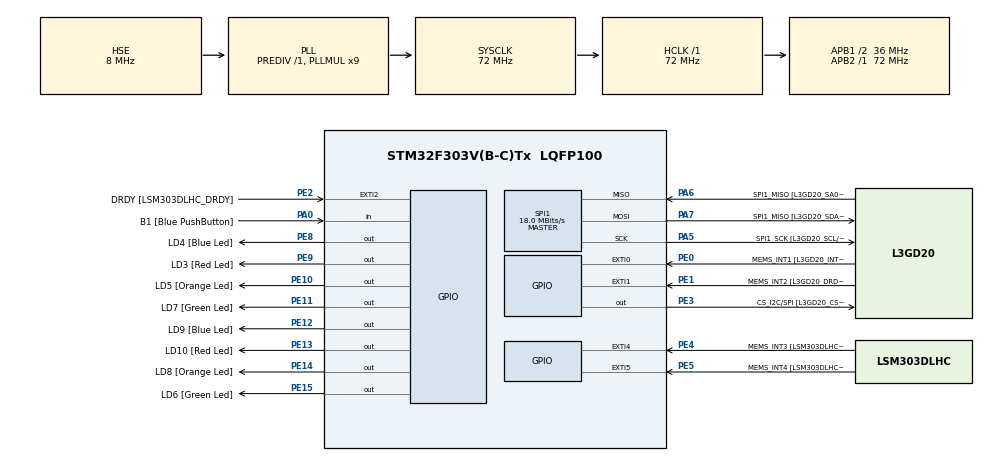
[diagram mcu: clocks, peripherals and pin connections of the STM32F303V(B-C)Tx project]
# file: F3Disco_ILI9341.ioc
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Mcu.Family=STM32F3
Mcu.Name=STM32F303V(B-C)Tx
Mcu.Package=LQFP100
NVIC.PriorityGroup=NVIC_PRIORITYGROUP_0
PA0.GPIO_Label=B1 [Blue PushButton]
PA0.GPIO_Mode=GPIO_MODE_INPUT
PA0.GPIO_PuPd=GPIO_NOPULL
PA0.Signal=GPIO_Input
PA11.GPIO_Label=DM
PA11.GPIO_Mode=GPIO_MODE_AF_PP
PA11.GPIO_PuPd=GPIO_NOPULL
PA11.GPIO_Speed=GPIO_SPEED_LOW
PA11.Signal=USB_DM
PA12.GPIO_Label=DP
PA12.GPIO_Mode=GPIO_MODE_AF_PP
PA12.GPIO_PuPd=GPIO_NOPULL
PA12.GPIO_Speed=GPIO_SPEED_LOW
PA12.Signal=USB_DP
PA13.GPIO_Label=SWDIO
PA13.Mode=Trace-Asynchronous_SW
PA13.Signal=SYS_JTMS-SWDIO
PA14.GPIO_Label=SWCLK
PA14.Mode=Trace-Asynchronous_SW
PA14.Signal=SYS_JTCK-SWCLK
PA5.GPIO_Label=SPI1_SCK [L3GD20_SCL/SPC]
PA5.GPIO_Mode=GPIO_MODE_AF_PP
PA5.GPIO_PuPd=GPIO_NOPULL
PA5.GPIO_Speed=GPIO_SPEED_LOW
PA5.Mode=Full_Duplex_Master
PA5.Signal=SPI1_SCK
PA6.GPIO_Label=SPI1_MISO [L3GD20_SA0/SDO]
PA6.GPIO_Mode=GPIO_MODE_AF_PP
PA6.GPIO_PuPd=GPIO_NOPULL
PA6.GPIO_Speed=GPIO_SPEED_LOW
PA6.Mode=Full_Duplex_Master
PA6.Signal=SPI1_MISO
PA7.GPIO_Label=SPI1_MISO [L3GD20_SDA/SDI/SDO]
PA7.GPIO_Mode=GPIO_MODE_AF_PP
PA7.GPIO_PuPd=GPIO_NOPULL
PA7.GPIO_Speed=GPIO_SPEED_LOW
PA7.Mode=Full_Duplex_Master
PA7.Signal=SPI1_MOSI
PB3.GPIO_Label=SWO
PB3.Mode=Trace-Asynchronous_SW
PB3.Signal=SYS_JTDO-TRACESWO
PB6.GPIO_FM6=__NULL
PB6.GPIO_Label=I2C1_SCL [LSM303DLHC_SCL]
PB6.GPIO_Mode=GPIO_MODE_AF_OD
PB6.GPIO_PuPd=GPIO_NOPULL
PB6.GPIO_PuPdOD=GPIO_PULLUP
PB6.GPIO_Speed=GPIO_SPEED_LOW
PB6.Signal=I2C1_SCL
PB7.GPIO_FM7=__NULL
PB7.GPIO_Label=I2C1_SDA [LSM303DLHC_SDA]
PB7.GPIO_Mode=GPIO_MODE_AF_OD
PB7.GPIO_PuPd=GPIO_NOPULL
PB7.GPIO_PuPdOD=GPIO_PULLUP
PB7.GPIO_Speed=GPIO_SPEED_LOW
PB7.Signal=I2C1_SDA
PC14-OSC32_IN.GPIO_Label=OSC32_IN
PC14-OSC32_IN.Signal=RCC_OSC32_IN
PC15-OSC32_OUT.GPIO_Label=OSC32_OUT
PC15-OSC32_OUT.Signal=RCC_OSC32_OUT
PE0.GPIO_Label=MEMS_INT1 [L3GD20_INT1]
PE0.GPIO_ModeDefaultEXTI=GPIO_MODE_EVT_RISING
PE0.GPIO_PuPd=GPIO_NOPULL
PE0.Signal=GPXTI0
PE1.GPIO_Label=MEMS_INT2 [L3GD20_DRDY/INT2]
PE1.GPIO_ModeDefaultEXTI=GPIO_MODE_EVT_RISING
PE1.GPIO_PuPd=GPIO_NOPULL
PE1.Signal=GPXTI1
PE10.GPIO_Label=LD5 [Orange Led]
PE10.GPIO_ModeDefaultOutputPP=GPIO_MODE_OUTPUT_PP
PE10.GPIO_PuPd=GPIO_NOPULL
PE10.GPIO_Speed=GPIO_SPEED_LOW
PE10.Signal=GPIO_Output
PE11.GPIO_Label=LD7 [Green Led]
PE11.GPIO_ModeDefaultOutputPP=GPIO_MODE_OUTPUT_PP
PE11.GPIO_PuPd=GPIO_NOPULL
PE11.GPIO_Speed=GPIO_SPEED_LOW
PE11.Signal=GPIO_Output
PE12.GPIO_Label=LD9 [Blue Led]
PE12.GPIO_ModeDefaultOutputPP=GPIO_MODE_OUTPUT_PP
PE12.GPIO_PuPd=GPIO_NOPULL
PE12.GPIO_Speed=GPIO_SPEED_LOW
PE12.Signal=GPIO_Output
PE13.GPIO_Label=LD10 [Red Led]
PE13.GPIO_ModeDefaultOutputPP=GPIO_MODE_OUTPUT_PP
PE13.GPIO_PuPd=GPIO_NOPULL
PE13.GPIO_Speed=GPIO_SPEED_LOW
PE13.Signal=GPIO_Output
PE14.GPIO_Label=LD8 [Orange Led]
PE14.GPIO_ModeDefaultOutputPP=GPIO_MODE_OUTPUT_PP
PE14.GPIO_PuPd=GPIO_NOPULL
PE14.GPIO_Speed=GPIO_SPEED_LOW
PE14.Signal=GPIO_Output
PE15.GPIO_Label=LD6 [Green Led]
PE15.GPIO_ModeDefaultOutputPP=GPIO_MODE_OUTPUT_PP
PE15.GPIO_PuPd=GPIO_NOPULL
PE15.GPIO_Speed=GPIO_SPEED_LOW
PE15.Signal=GPIO_Output
PE2.GPIO_Label=DRDY [LSM303DLHC_DRDY]
PE2.GPIO_ModeDefaultEXTI=GPIO_MODE_EVT_RISING
PE2.GPIO_PuPd=GPIO_NOPULL
PE2.Signal=GPXTI2
PE3.GPIO_Label=CS_I2C/SPI [L3GD20_CS_I2C/SPI]
PE3.GPIO_ModeDefaultOutputPP=GPIO_MODE_OUTPUT_PP
PE3.GPIO_PuPd=GPIO_NOPULL
PE3.GPIO_Speed=GPIO_SPEED_LOW
PE3.Signal=GPIO_Output
PE4.GPIO_Label=MEMS_INT3 [LSM303DLHC_INT1]
PE4.GPIO_ModeDefaultEXTI=GPIO_MODE_EVT_RISING
PE4.GPIO_PuPd=GPIO_NOPULL
PE4.Signal=GPXTI4
PE5.GPIO_Label=MEMS_INT4 [LSM303DLHC_INT2]
PE5.GPIO_ModeDefaultEXTI=GPIO_MODE_EVT_RISING
PE5.GPIO_PuPd=GPIO_NOPULL
PE5.Signal=GPXTI5
PE8.GPIO_Label=LD4 [Blue Led]
PE8.GPIO_ModeDefaultOutputPP=GPIO_MODE_OUTPUT_PP
PE8.GPIO_PuPd=GPIO_NOPULL
PE8.GPIO_Speed=GPIO_SPEED_LOW
PE8.Signal=GPIO_Output
PE9.GPIO_Label=LD3 [Red Led]
PE9.GPIO_ModeDefaultOutputPP=GPIO_MODE_OUTPUT_PP
PE9.GPIO_PuPd=GPIO_NOPULL
PE9.GPIO_Speed=GPIO_SPEED_LOW
PE9.Signal=GPIO_Output
PF0-OSC_IN.Mode=HSE-External-Oscillator
PF0-OSC_IN.Signal=RCC_OSC_IN
PF1-OSC_OUT.GPIO_Label=OSC_OUT
PF1-OSC_OUT.Mode=HSE-External-Oscillator
PF1-OSC_OUT.Signal=RCC_OSC_OUT
ProjectManager.TargetToolchain=MDK-ARM V5
RCC.AHBFreq_Value=72000000
RCC.APB1CLKDivider=RCC_HCLK_DIV2
RCC.APB1Freq_Value=36000000
RCC.APB1TimFreq_Value=72000000
RCC.APB2Freq_Value=72000000
RCC.APB2TimFreq_Value=72000000
RCC.CortexFreq_Value=9000000
RCC.HCLKFreq_Value=72000000
RCC.HSE_VALUE=8000000
RCC.HSIState=RCC_HSI_ON
RCC.HSI_VALUE=8000000
RCC.LSE_VALUE=32768
RCC.PLLMUL=RCC_PLL_MUL9
RCC.PLLSourceVirtual=RCC_PLLSOURCE_HSE
RCC.SYSCLKFreq_VALUE=72000000
RCC.SYSCLKSource=RCC_SYSCLKSOURCE_PLLCLK
RCC.SYSCLKSourceVirtual=RCC_SYSCLKSOURCE_PLLCLK
RCC.USBFreq_Value=72000000
SPI1.BaudRatePrescaler=SPI_BAUDRATEPRESCALER_4
SPI1.CalculateBaudRate=18.0 MBits/s
SPI1.DataSize=SPI_DATASIZE_8BIT
SPI1.Mode=SPI_MODE_MASTER

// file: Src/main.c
/**
  ******************************************************************************
  * File Name          : main.c
  * Date               : 14/05/2015 17:09:52
  * Description        : Main program body
  ******************************************************************************
  *
  * COPYRIGHT(c) 2015 STMicroelectronics
  *
  * Redistribution and use in source and binary forms, with or without modification,
  * are permitted provided that the following conditions are met:
  *   1. Redistributions of source code must retain the above copyright notice,
  *      this list of conditions and the following disclaimer.
  *   2. Redistributions in binary form must reproduce the above copyright notice,
  *      this list of conditions and the following disclaimer in the documentation
  *      and/or other materials provided with the distribution.
  *   3. Neither the name of STMicroelectronics nor the names of its contributors
  *      may be used to endorse or promote products derived from this software
  *      without specific prior written permission.
  *
  * THIS SOFTWARE IS PROVIDED BY THE COPYRIGHT HOLDERS AND CONTRIBUTORS "AS IS"
  * AND ANY EXPRESS OR IMPLIED WARRANTIES, INCLUDING, BUT NOT LIMITED TO, THE
  * IMPLIED WARRANTIES OF MERCHANTABILITY AND FITNESS FOR A PARTICULAR PURPOSE ARE
  * DISCLAIMED. IN NO EVENT SHALL THE COPYRIGHT HOLDER OR CONTRIBUTORS BE LIABLE
  * FOR ANY DIRECT, INDIRECT, INCIDENTAL, SPECIAL, EXEMPLARY, OR CONSEQUENTIAL
  * DAMAGES (INCLUDING, BUT NOT LIMITED TO, PROCUREMENT OF SUBSTITUTE GOODS OR
  * SERVICES; LOSS OF USE, DATA, OR PROFITS; OR BUSINESS INTERRUPTION) HOWEVER
  * CAUSED AND ON ANY THEORY OF LIABILITY, WHETHER IN CONTRACT, STRICT LIABILITY,
  * OR TORT (INCLUDING NEGLIGENCE OR OTHERWISE) ARISING IN ANY WAY OUT OF THE USE
  * OF THIS SOFTWARE, EVEN IF ADVISED OF THE POSSIBILITY OF SUCH DAMAGE.
  *
  ******************************************************************************
  */

#include "stm32f3xx_hal.h"
#include "stm32f3xx_hal_spi.h"

#include "tm_stm32f3_fonts.h"
#include "tm_stm32f3_ili9341.h"
#include "delay.h"
#include "youbeep_3.h"

#define led3_h  HAL_GPIO_WritePin ( GPIOE , GPIO_PIN_9  , GPIO_PIN_SET		);
#define led3_l	HAL_GPIO_WritePin ( GPIOE , GPIO_PIN_9  , GPIO_PIN_RESET	);
#define led4_h  HAL_GPIO_WritePin ( GPIOE , GPIO_PIN_8  , GPIO_PIN_SET		);
#define led4_l	HAL_GPIO_WritePin ( GPIOE , GPIO_PIN_8  , GPIO_PIN_RESET	);
#define led5_h  HAL_GPIO_WritePin ( GPIOE , GPIO_PIN_10 , GPIO_PIN_SET		);
#define led5_l	HAL_GPIO_WritePin ( GPIOE , GPIO_PIN_10 , GPIO_PIN_RESET	);
#define led6_h  HAL_GPIO_WritePin ( GPIOE , GPIO_PIN_15 , GPIO_PIN_SET		);
#define led6_l	HAL_GPIO_WritePin ( GPIOE , GPIO_PIN_15 , GPIO_PIN_RESET	);
#define led7_h  HAL_GPIO_WritePin ( GPIOE , GPIO_PIN_11 , GPIO_PIN_SET		);
#define led7_l	HAL_GPIO_WritePin ( GPIOE , GPIO_PIN_11 , GPIO_PIN_RESET	);
#define led8_h  HAL_GPIO_WritePin ( GPIOE , GPIO_PIN_14 , GPIO_PIN_SET		);
#define led8_l	HAL_GPIO_WritePin ( GPIOE , GPIO_PIN_14 , GPIO_PIN_RESET	);
#define led9_h  HAL_GPIO_WritePin ( GPIOE , GPIO_PIN_12 , GPIO_PIN_SET		);
#define led9_l	HAL_GPIO_WritePin ( GPIOE , GPIO_PIN_12 , GPIO_PIN_RESET	);
#define led10_h HAL_GPIO_WritePin ( GPIOE , GPIO_PIN_13 , GPIO_PIN_SET		);
#define led10_l	HAL_GPIO_WritePin ( GPIOE , GPIO_PIN_13 , GPIO_PIN_RESET	);

SPI_HandleTypeDef hspi1;

void SystemClock_Config(void);
static void MX_GPIO_Init(void);
static void MX_SPI1_Init(void);

int main(void)
{

  /* MCU Configuration----------------------------------------------------------*/

  /* Reset of all peripherals, Initializes the Flash interface and the Systick. */
  HAL_Init();

  /* Configure the system clock */
  SystemClock_Config();
	TM_Delay_Init();
  /* Initialize all configured peripherals */
  MX_GPIO_Init();

  MX_SPI1_Init();

  // CODE
	// Initialize ILI9341
	TM_ILI9341_Init();
	// Rotate LCD for 90 degrees
	TM_ILI9341_Rotate(TM_ILI9341_Orientation_Landscape_1);
	//TM_ILI9341_Fill( ILI9341_COLOR_YOUBEEP);
	//TM_ILI9341_Puts(10,10,"Funca",&TM_Font_7x10,ILI9341_COLOR_BLACK,ILI9341_TRANSPARENT);
	drawbmp(youbeep_3,TM_ILI9341_Image_Horizontal);

	TM_ILI9341_Puts(10,10,"isto e uma string com paragrafo",&TM_Font_16x26,ILI9341_COLOR_WHITE,ILI9341_TRANSPARENT);
	while (1)
  {
		HAL_GPIO_TogglePin(GPIOE,GPIO_PIN_15);
		TM_DelayMillis(500);
  }

}

/** System Clock Configuration
*/
void SystemClock_Config(void)
{

  RCC_OscInitTypeDef RCC_OscInitStruct;
  RCC_ClkInitTypeDef RCC_ClkInitStruct;

  RCC_OscInitStruct.OscillatorType = RCC_OSCILLATORTYPE_HSE;
  RCC_OscInitStruct.HSEState = RCC_HSE_ON;
  RCC_OscInitStruct.HSEPredivValue = RCC_HSE_PREDIV_DIV1;
  RCC_OscInitStruct.PLL.PLLState = RCC_PLL_ON;
  RCC_OscInitStruct.PLL.PLLSource = RCC_PLLSOURCE_HSE;
  RCC_OscInitStruct.PLL.PLLMUL = RCC_PLL_MUL9;
  HAL_RCC_OscConfig(&RCC_OscInitStruct);

  RCC_ClkInitStruct.ClockType = RCC_CLOCKTYPE_SYSCLK|RCC_CLOCKTYPE_PCLK1;
  RCC_ClkInitStruct.SYSCLKSource = RCC_SYSCLKSOURCE_PLLCLK;
  RCC_ClkInitStruct.AHBCLKDivider = RCC_SYSCLK_DIV1;
  RCC_ClkInitStruct.APB1CLKDivider = RCC_HCLK_DIV2;
  RCC_ClkInitStruct.APB2CLKDivider = RCC_HCLK_DIV1;
  HAL_RCC_ClockConfig(&RCC_ClkInitStruct, FLASH_LATENCY_2);

  __SYSCFG_CLK_ENABLE();

}

/* SPI1 init function */
void MX_SPI1_Init(void)
{

  hspi1.Instance = SPI1;
  hspi1.Init.Mode = SPI_MODE_MASTER;
  hspi1.Init.Direction = SPI_DIRECTION_2LINES;
  hspi1.Init.DataSize = SPI_DATASIZE_8BIT;
  hspi1.Init.CLKPolarity = SPI_POLARITY_LOW;								//default LOW
  hspi1.Init.CLKPhase = SPI_PHASE_1EDGE;										//default 1Edge
  hspi1.Init.NSS = SPI_NSS_SOFT;
  hspi1.Init.BaudRatePrescaler = SPI_BAUDRATEPRESCALER_2;
  hspi1.Init.FirstBit = SPI_FIRSTBIT_MSB;
  hspi1.Init.TIMode = SPI_TIMODE_DISABLED;
  hspi1.Init.CRCCalculation = SPI_CRCCALCULATION_DISABLED;
  hspi1.Init.NSSPMode = SPI_NSS_PULSE_ENABLED;
  HAL_SPI_Init(&hspi1);

}

/** Configure pins as
        * Analog
        * Input
        * Output
        * EVENT_OUT
        * EXTI
     PA11   ------> USB_DM
     PA12   ------> USB_DP
     PB6   ------> I2C1_SCL
     PB7   ------> I2C1_SDA
*/
void MX_GPIO_Init(void)
{

  GPIO_InitTypeDef GPIO_InitStruct;

  /* GPIO Ports Clock Enable */
  __GPIOE_CLK_ENABLE();
  __GPIOC_CLK_ENABLE();
  __GPIOF_CLK_ENABLE();
  __GPIOA_CLK_ENABLE();
  __GPIOB_CLK_ENABLE();

  /*Configure GPIO pins : PE2 PE4 PE5 PE0
                           PE1 */
  /*GPIO_InitStruct.Pin = GPIO_PIN_2|GPIO_PIN_4|GPIO_PIN_5|GPIO_PIN_0
                          |GPIO_PIN_1;
  GPIO_InitStruct.Mode = GPIO_MODE_EVT_RISING;
  GPIO_InitStruct.Pull = GPIO_NOPULL;
  HAL_GPIO_Init(GPIOE, &GPIO_InitStruct);*/

  /*Configure GPIO pins : PE3 PE8 PE9 PE10
                           PE11 PE12 PE13 PE14
                           PE15 */
  GPIO_InitStruct.Pin = GPIO_PIN_3|GPIO_PIN_8|GPIO_PIN_9|GPIO_PIN_10
                          |GPIO_PIN_11|GPIO_PIN_12|GPIO_PIN_13|GPIO_PIN_14
                          |GPIO_PIN_15;
  GPIO_InitStruct.Mode = GPIO_MODE_OUTPUT_PP;
  GPIO_InitStruct.Pull = GPIO_NOPULL;
  GPIO_InitStruct.Speed = GPIO_SPEED_LOW;
  HAL_GPIO_Init(GPIOE, &GPIO_InitStruct);

  /*Configure GPIO pin : PA0 */
  GPIO_InitStruct.Pin = GPIO_PIN_0;
  GPIO_InitStruct.Mode = GPIO_MODE_INPUT;
  GPIO_InitStruct.Pull = GPIO_NOPULL;
  HAL_GPIO_Init(GPIOA, &GPIO_InitStruct);

	/*Configure GPIO pin : PA1 - CS | PA2 - DC | PA3 - RST  */
	GPIO_InitStruct.Pin = GPIO_PIN_1 |GPIO_PIN_2;
  GPIO_InitStruct.Mode = GPIO_MODE_OUTPUT_PP;
  GPIO_InitStruct.Pull = GPIO_NOPULL;
  GPIO_InitStruct.Speed = GPIO_SPEED_MEDIUM;
  HAL_GPIO_Init(GPIOA, &GPIO_InitStruct);

	GPIO_InitStruct.Pin = GPIO_PIN_3;
  GPIO_InitStruct.Mode = GPIO_MODE_OUTPUT_PP;
  GPIO_InitStruct.Pull = GPIO_PULLUP;
  GPIO_InitStruct.Speed = GPIO_SPEED_LOW;
  HAL_GPIO_Init(GPIOA, &GPIO_InitStruct);

  /*Configure GPIO pins : PA11 PA12 */
  /*GPIO_InitStruct.Pin = GPIO_PIN_11|GPIO_PIN_12;
  GPIO_InitStruct.Mode = GPIO_MODE_AF_PP;
  GPIO_InitStruct.Pull = GPIO_NOPULL;
  GPIO_InitStruct.Speed = GPIO_SPEED_LOW;
  GPIO_InitStruct.Alternate = GPIO_AF14_USB;
  HAL_GPIO_Init(GPIOA, &GPIO_InitStruct);*/

  /*Configure GPIO pins : PB6 PB7 */
  /*GPIO_InitStruct.Pin = GPIO_PIN_6|GPIO_PIN_7;
  GPIO_InitStruct.Mode = GPIO_MODE_AF_OD;
  GPIO_InitStruct.Pull = GPIO_PULLUP;
  GPIO_InitStruct.Speed = GPIO_SPEED_LOW;
  GPIO_InitStruct.Alternate = GPIO_AF4_I2C1;
  HAL_GPIO_Init(GPIOB, &GPIO_InitStruct);*/

}

/************************ (C) COPYRIGHT STMicroelectronics *****END OF FILE****/
